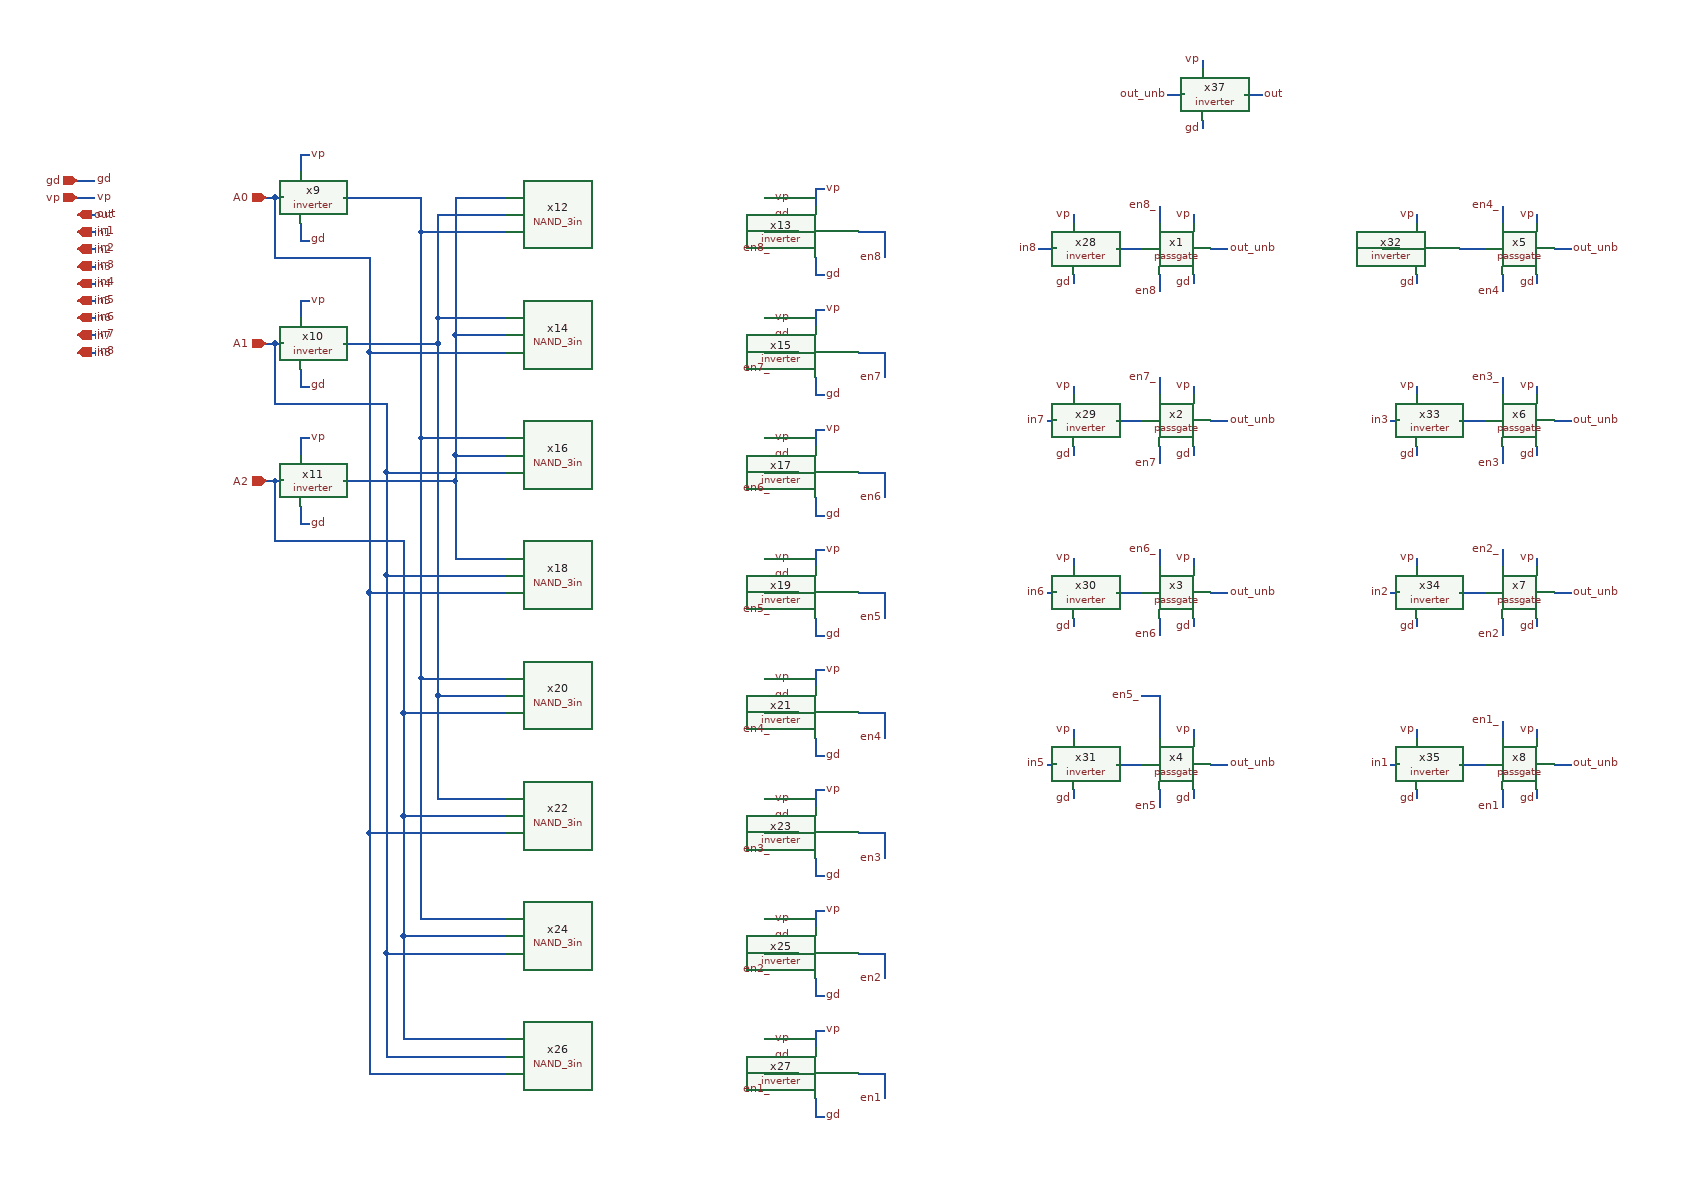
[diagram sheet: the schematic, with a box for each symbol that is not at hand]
v {xschem version=3.4.8RC file_version=1.3}
G {}
K {}
V {}
S {}
F {}
E {}
N -970 -290 -950 -290 {lab=gd}
N -970 -270 -950 -270 {lab=vp}
N -970 -250 -950 -250 {lab=out}
N -970 -230 -950 -230 {lab=in1}
N -970 -210 -950 -210 {lab=in2}
N -970 -190 -950 -190 {lab=in3}
N -970 -170 -950 -170 {lab=in4}
N -970 -130 -950 -130 {lab=in6}
N -970 -110 -950 -110 {lab=in7}
N -970 -90 -950 -90 {lab=in8}
N 290 -260 290 -240 {lab=en8_}
N 290 -180 290 -160 {lab=en8}
N 330 -180 330 -170 {lab=gd}
N 330 -250 330 -240 {lab=vp}
N 350 -210 370 -210 {lab=out_unb}
N 290 -60 290 -40 {lab=en7_}
N 290 20 290 40 {lab=en7}
N 330 20 330 30 {lab=gd}
N 330 -50 330 -40 {lab=vp}
N 160 -10 170 -10 {lab=in7}
N 350 -10 370 -10 {lab=out_unb}
N -970 -150 -950 -150 {lab=in5}
N 290 140 290 160 {lab=en6_}
N 290 220 290 240 {lab=en6}
N 330 220 330 230 {lab=gd}
N 330 150 330 160 {lab=vp}
N 160 190 170 190 {lab=in6}
N 350 190 370 190 {lab=out_unb}
N 290 420 290 440 {lab=en5}
N 330 420 330 430 {lab=gd}
N 330 350 330 360 {lab=vp}
N 160 390 170 390 {lab=in5}
N 350 390 370 390 {lab=out_unb}
N 690 -260 690 -240 {lab=en4_}
N 690 -180 690 -160 {lab=en4}
N 730 -180 730 -170 {lab=gd}
N 730 -250 730 -240 {lab=vp}
N 750 -210 770 -210 {lab=out_unb}
N 690 -60 690 -40 {lab=en3_}
N 690 20 690 40 {lab=en3}
N 730 20 730 30 {lab=gd}
N 730 -50 730 -40 {lab=vp}
N 560 -10 570 -10 {lab=in3}
N 750 -10 770 -10 {lab=out_unb}
N 690 140 690 160 {lab=en2_}
N 690 220 690 240 {lab=en2}
N 730 220 730 230 {lab=gd}
N 730 150 730 160 {lab=vp}
N 750 190 770 190 {lab=out_unb}
N 690 340 690 360 {lab=en1_}
N 690 420 690 440 {lab=en1}
N 730 420 730 430 {lab=gd}
N 730 350 730 360 {lab=vp}
N 750 390 770 390 {lab=out_unb}
N -710 -320 -700 -320 {lab=vp}
N -710 -320 -710 -300 {lab=vp}
N -710 -220 -700 -220 {lab=gd}
N -710 -240 -710 -220 {lab=gd}
N -740 -270 -730 -270 {lab=A0}
N -710 -150 -700 -150 {lab=vp}
N -710 -150 -710 -130 {lab=vp}
N -710 -50 -700 -50 {lab=gd}
N -710 -70 -710 -50 {lab=gd}
N -740 -100 -730 -100 {lab=A1}
N -710 10 -700 10 {lab=vp}
N -710 10 -710 30 {lab=vp}
N -710 110 -700 110 {lab=gd}
N -710 90 -710 110 {lab=gd}
N -740 60 -730 60 {lab=A2}
N -170 -270 -160 -270 {lab=vp}
N -170 -250 -160 -250 {lab=gd}
N -110 -280 -100 -280 {lab=vp}
N -110 -280 -110 -260 {lab=vp}
N -110 -180 -100 -180 {lab=gd}
N -110 -200 -110 -180 {lab=gd}
N -160 -230 -130 -230 {lab=en8_}
N -60 -230 -30 -230 {lab=en8}
N -160 -230 -160 -210 {lab=en8_}
N -170 -230 -160 -230 {lab=en8_}
N -30 -230 -30 -200 {lab=en8}
N -170 -130 -160 -130 {lab=vp}
N -170 -110 -160 -110 {lab=gd}
N -110 -140 -100 -140 {lab=vp}
N -110 -140 -110 -120 {lab=vp}
N -110 -40 -100 -40 {lab=gd}
N -110 -60 -110 -40 {lab=gd}
N -160 -90 -130 -90 {lab=en7_}
N -60 -90 -30 -90 {lab=en7}
N -160 -90 -160 -70 {lab=en7_}
N -170 -90 -160 -90 {lab=en7_}
N -30 -90 -30 -60 {lab=en7}
N -170 10 -160 10 {lab=vp}
N -170 30 -160 30 {lab=gd}
N -110 0 -100 0 {lab=vp}
N -110 0 -110 20 {lab=vp}
N -110 100 -100 100 {lab=gd}
N -110 80 -110 100 {lab=gd}
N -160 50 -130 50 {lab=en6_}
N -60 50 -30 50 {lab=en6}
N -160 50 -160 70 {lab=en6_}
N -170 50 -160 50 {lab=en6_}
N -30 50 -30 80 {lab=en6}
N -170 150 -160 150 {lab=vp}
N -170 170 -160 170 {lab=gd}
N -110 140 -100 140 {lab=vp}
N -110 140 -110 160 {lab=vp}
N -110 240 -100 240 {lab=gd}
N -110 220 -110 240 {lab=gd}
N -160 190 -130 190 {lab=en5_}
N -60 190 -30 190 {lab=en5}
N -160 190 -160 210 {lab=en5_}
N -170 190 -160 190 {lab=en5_}
N -30 190 -30 220 {lab=en5}
N -170 290 -160 290 {lab=vp}
N -170 310 -160 310 {lab=gd}
N -110 280 -100 280 {lab=vp}
N -110 280 -110 300 {lab=vp}
N -110 380 -100 380 {lab=gd}
N -110 360 -110 380 {lab=gd}
N -160 330 -130 330 {lab=en4_}
N -60 330 -30 330 {lab=en4}
N -160 330 -160 350 {lab=en4_}
N -170 330 -160 330 {lab=en4_}
N -30 330 -30 360 {lab=en4}
N -170 430 -160 430 {lab=vp}
N -170 450 -160 450 {lab=gd}
N -110 420 -100 420 {lab=vp}
N -110 420 -110 440 {lab=vp}
N -110 520 -100 520 {lab=gd}
N -110 500 -110 520 {lab=gd}
N -160 470 -130 470 {lab=en3_}
N -60 470 -30 470 {lab=en3}
N -160 470 -160 490 {lab=en3_}
N -170 470 -160 470 {lab=en3_}
N -30 470 -30 500 {lab=en3}
N -170 570 -160 570 {lab=vp}
N -170 590 -160 590 {lab=gd}
N -110 560 -100 560 {lab=vp}
N -110 560 -110 580 {lab=vp}
N -110 660 -100 660 {lab=gd}
N -110 640 -110 660 {lab=gd}
N -160 610 -130 610 {lab=en2_}
N -60 610 -30 610 {lab=en2}
N -160 610 -160 630 {lab=en2_}
N -170 610 -160 610 {lab=en2_}
N -30 610 -30 640 {lab=en2}
N -170 710 -160 710 {lab=vp}
N -170 730 -160 730 {lab=gd}
N -110 700 -100 700 {lab=vp}
N -110 700 -110 720 {lab=vp}
N -110 800 -100 800 {lab=gd}
N -110 780 -110 800 {lab=gd}
N -160 750 -130 750 {lab=en1_}
N -60 750 -30 750 {lab=en1}
N -160 750 -160 770 {lab=en1_}
N -170 750 -160 750 {lab=en1_}
N -30 750 -30 780 {lab=en1}
N -630 470 -630 750 {lab=A0}
N -740 -270 -740 -200 {lab=A0}
N -750 -270 -740 -270 {lab=A0}
N -740 -200 -630 -200 {lab=A0}
N -740 -100 -740 -30 {lab=A1}
N -750 -100 -740 -100 {lab=A1}
N -740 -30 -610 -30 {lab=A1}
N -740 60 -740 130 {lab=A2}
N -750 60 -740 60 {lab=A2}
N -740 130 -590 130 {lab=A2}
N -660 -270 -570 -270 {lab=#net1}
N -660 -100 -550 -100 {lab=#net2}
N -550 -130 -550 -100 {lab=#net2}
N -660 60 -530 60 {lab=#net3}
N -530 30 -530 60 {lab=#net3}
N -570 -230 -470 -230 {lab=#net1}
N -570 -270 -570 -230 {lab=#net1}
N -550 -250 -470 -250 {lab=#net2}
N -530 -270 -470 -270 {lab=#net3}
N -570 10 -470 10 {lab=#net1}
N -570 -230 -570 10 {lab=#net1}
N -570 290 -470 290 {lab=#net1}
N -570 10 -570 290 {lab=#net1}
N -570 570 -470 570 {lab=#net1}
N -570 290 -570 570 {lab=#net1}
N -550 -130 -470 -130 {lab=#net2}
N -550 -250 -550 -130 {lab=#net2}
N -550 430 -470 430 {lab=#net2}
N -550 310 -550 430 {lab=#net2}
N -550 310 -470 310 {lab=#net2}
N -550 -100 -550 310 {lab=#net2}
N -530 -110 -470 -110 {lab=#net3}
N -530 -270 -530 -110 {lab=#net3}
N -530 30 -470 30 {lab=#net3}
N -530 -110 -530 30 {lab=#net3}
N -530 150 -470 150 {lab=#net3}
N -530 60 -530 150 {lab=#net3}
N -590 710 -470 710 {lab=A2}
N -590 590 -590 710 {lab=A2}
N -590 590 -470 590 {lab=A2}
N -590 450 -590 590 {lab=A2}
N -590 450 -470 450 {lab=A2}
N -590 330 -590 450 {lab=A2}
N -590 330 -470 330 {lab=A2}
N -590 130 -590 330 {lab=A2}
N -610 730 -470 730 {lab=A1}
N -610 610 -610 730 {lab=A1}
N -610 610 -470 610 {lab=A1}
N -610 170 -610 610 {lab=A1}
N -610 50 -470 50 {lab=A1}
N -610 -30 -610 50 {lab=A1}
N -610 170 -470 170 {lab=A1}
N -610 50 -610 170 {lab=A1}
N -630 -90 -470 -90 {lab=A0}
N -630 -200 -630 -90 {lab=A0}
N -630 190 -470 190 {lab=A0}
N -630 -90 -630 190 {lab=A0}
N -630 470 -470 470 {lab=A0}
N -630 190 -630 470 {lab=A0}
N -630 750 -470 750 {lab=A0}
N 240 -210 270 -210 {lab=#net4}
N 190 -250 190 -240 {lab=vp}
N 190 -180 190 -170 {lab=gd}
N 150 -210 170 -210 {lab=in8}
N 240 -10 270 -10 {lab=#net5}
N 190 -50 190 -40 {lab=vp}
N 190 20 190 30 {lab=gd}
N 240 190 270 190 {lab=#net6}
N 190 150 190 160 {lab=vp}
N 190 220 190 230 {lab=gd}
N 240 390 270 390 {lab=#net7}
N 190 350 190 360 {lab=vp}
N 190 420 190 430 {lab=gd}
N 560 190 570 190 {lab=in2}
N 560 390 570 390 {lab=in1}
N 640 -210 670 -210 {lab=#net8}
N 590 -250 590 -240 {lab=vp}
N 590 -180 590 -170 {lab=gd}
N 550 -210 570 -210 {lab=in4}
N 640 -10 670 -10 {lab=#net9}
N 590 -50 590 -40 {lab=vp}
N 590 20 590 30 {lab=gd}
N 640 190 670 190 {lab=#net10}
N 590 150 590 160 {lab=vp}
N 590 220 590 230 {lab=gd}
N 640 390 670 390 {lab=#net11}
N 590 350 590 360 {lab=vp}
N 590 420 590 430 {lab=gd}
N 340 -430 340 -420 {lab=vp}
N 340 -360 340 -350 {lab=gd}
N 390 -390 410 -390 {lab=out}
N 300 -390 320 -390 {lab=out_unb}
N 270 310 290 310 {lab=en5_}
N 290 310 290 360 {lab=en5_}
C {/foss/designs/CHIP-PLL/divider/schematics/passgate.sym} 290 -190 0 0 {name=x1}
C {iopin.sym} -970 -290 2 0 {name=p1 lab=gd}
C {lab_pin.sym} -950 -290 2 0 {name=p4 sig_type=std_logic lab=gd}
C {iopin.sym} -970 -270 2 0 {name=p5 lab=vp}
C {lab_pin.sym} -950 -270 2 0 {name=p6 sig_type=std_logic lab=vp}
C {opin.sym} -970 -250 2 0 {name=p2 lab=out}
C {lab_pin.sym} -950 -250 2 0 {name=p3 sig_type=std_logic lab=out}
C {ipin.sym} -970 -230 2 1 {name=p7 lab=in1}
C {lab_pin.sym} -950 -230 2 0 {name=p8 sig_type=std_logic lab=in1}
C {ipin.sym} -970 -210 2 1 {name=p9 lab=in2}
C {lab_pin.sym} -950 -210 2 0 {name=p10 sig_type=std_logic lab=in2}
C {ipin.sym} -970 -190 2 1 {name=p11 lab=in3}
C {lab_pin.sym} -950 -190 2 0 {name=p12 sig_type=std_logic lab=in3}
C {ipin.sym} -970 -170 2 1 {name=p13 lab=in4}
C {lab_pin.sym} -950 -170 2 0 {name=p14 sig_type=std_logic lab=in4}
C {ipin.sym} -970 -150 2 1 {name=p15 lab=in5}
C {lab_pin.sym} -950 -150 2 0 {name=p16 sig_type=std_logic lab=in5}
C {ipin.sym} -970 -130 2 1 {name=p17 lab=in6}
C {lab_pin.sym} -950 -130 2 0 {name=p18 sig_type=std_logic lab=in6}
C {ipin.sym} -970 -110 2 1 {name=p19 lab=in7}
C {lab_pin.sym} -950 -110 2 0 {name=p20 sig_type=std_logic lab=in7}
C {ipin.sym} -970 -90 2 1 {name=p21 lab=in8}
C {lab_pin.sym} -950 -90 2 0 {name=p22 sig_type=std_logic lab=in8}
C {lab_pin.sym} 330 -170 3 0 {name=p23 sig_type=std_logic lab=gd}
C {lab_pin.sym} 290 -260 1 0 {name=p25 sig_type=std_logic lab=en8_}
C {lab_pin.sym} 290 -160 3 0 {name=p26 sig_type=std_logic lab=en8}
C {lab_pin.sym} 150 -210 0 0 {name=p27 sig_type=std_logic lab=in8}
C {lab_pin.sym} 370 -210 2 0 {name=p28 sig_type=std_logic lab=out_unb}
C {/foss/designs/CHIP-PLL/divider/schematics/passgate.sym} 290 10 0 0 {name=x2}
C {lab_pin.sym} 330 30 3 0 {name=p29 sig_type=std_logic lab=gd}
C {lab_pin.sym} 290 -60 1 0 {name=p31 sig_type=std_logic lab=en7_}
C {lab_pin.sym} 290 40 3 0 {name=p32 sig_type=std_logic lab=en7}
C {lab_pin.sym} 160 -10 0 0 {name=p33 sig_type=std_logic lab=in7}
C {lab_pin.sym} 370 -10 2 0 {name=p34 sig_type=std_logic lab=out_unb}
C {/foss/designs/CHIP-PLL/divider/schematics/passgate.sym} 290 210 0 0 {name=x3}
C {lab_pin.sym} 330 230 3 0 {name=p35 sig_type=std_logic lab=gd}
C {lab_pin.sym} 290 140 1 0 {name=p37 sig_type=std_logic lab=en6_}
C {lab_pin.sym} 290 240 3 0 {name=p38 sig_type=std_logic lab=en6}
C {lab_pin.sym} 160 190 0 0 {name=p39 sig_type=std_logic lab=in6
}
C {lab_pin.sym} 370 190 2 0 {name=p40 sig_type=std_logic lab=out_unb}
C {/foss/designs/CHIP-PLL/divider/schematics/passgate.sym} 290 410 0 0 {name=x4}
C {lab_pin.sym} 330 430 3 0 {name=p41 sig_type=std_logic lab=gd}
C {lab_pin.sym} 290 440 3 0 {name=p44 sig_type=std_logic lab=en5}
C {lab_pin.sym} 160 390 0 0 {name=p45 sig_type=std_logic lab=in5}
C {lab_pin.sym} 370 390 2 0 {name=p46 sig_type=std_logic lab=out_unb}
C {/foss/designs/CHIP-PLL/divider/schematics/passgate.sym} 690 -190 0 0 {name=x5}
C {lab_pin.sym} 730 -170 3 0 {name=p47 sig_type=std_logic lab=gd}
C {lab_pin.sym} 690 -260 1 0 {name=p49 sig_type=std_logic lab=en4_}
C {lab_pin.sym} 690 -160 3 0 {name=p50 sig_type=std_logic lab=en4}
C {lab_pin.sym} 560 -210 0 0 {name=p51 sig_type=std_logic lab=in4}
C {lab_pin.sym} 770 -210 2 0 {name=p52 sig_type=std_logic lab=out_unb}
C {/foss/designs/CHIP-PLL/divider/schematics/passgate.sym} 690 10 0 0 {name=x6}
C {lab_pin.sym} 730 30 3 0 {name=p53 sig_type=std_logic lab=gd}
C {lab_pin.sym} 690 -60 1 0 {name=p55 sig_type=std_logic lab=en3_}
C {lab_pin.sym} 690 40 3 0 {name=p56 sig_type=std_logic lab=en3}
C {lab_pin.sym} 560 -10 0 0 {name=p57 sig_type=std_logic lab=in3}
C {lab_pin.sym} 770 -10 2 0 {name=p58 sig_type=std_logic lab=out_unb}
C {/foss/designs/CHIP-PLL/divider/schematics/passgate.sym} 690 210 0 0 {name=x7}
C {lab_pin.sym} 730 230 3 0 {name=p59 sig_type=std_logic lab=gd}
C {lab_pin.sym} 690 140 1 0 {name=p61 sig_type=std_logic lab=en2_}
C {lab_pin.sym} 690 240 3 0 {name=p62 sig_type=std_logic lab=en2}
C {lab_pin.sym} 560 190 0 0 {name=p63 sig_type=std_logic lab=in2}
C {lab_pin.sym} 770 190 2 0 {name=p64 sig_type=std_logic lab=out_unb}
C {/foss/designs/CHIP-PLL/divider/schematics/passgate.sym} 690 410 0 0 {name=x8}
C {lab_pin.sym} 730 430 3 0 {name=p65 sig_type=std_logic lab=gd}
C {lab_pin.sym} 690 340 1 0 {name=p67 sig_type=std_logic lab=en1_
_}
C {lab_pin.sym} 690 440 3 0 {name=p68 sig_type=std_logic lab=en1}
C {lab_pin.sym} 560 390 0 0 {name=p69 sig_type=std_logic lab=in1}
C {lab_pin.sym} 770 390 2 0 {name=p70 sig_type=std_logic lab=out_unb}
C {/foss/designs/CHIP-PLL/divider/schematics/inverter.sym} -710 -270 0 0 {name=x9}
C {lab_pin.sym} -700 -220 2 0 {name=p71 sig_type=std_logic lab=gd}
C {lab_pin.sym} -700 -320 2 0 {name=p72 sig_type=std_logic lab=vp}
C {ipin.sym} -750 -270 0 0 {name=p73 lab=A0}
C {/foss/designs/CHIP-PLL/divider/schematics/inverter.sym} -710 -100 0 0 {name=x10}
C {lab_pin.sym} -700 -50 2 0 {name=p74 sig_type=std_logic lab=gd}
C {lab_pin.sym} -700 -150 2 0 {name=p75 sig_type=std_logic lab=vp}
C {ipin.sym} -750 -100 0 0 {name=p76 lab=A1}
C {/foss/designs/CHIP-PLL/divider/schematics/inverter.sym} -710 60 0 0 {name=x11}
C {lab_pin.sym} -700 110 2 0 {name=p77 sig_type=std_logic lab=gd}
C {lab_pin.sym} -700 10 2 0 {name=p78 sig_type=std_logic lab=vp}
C {ipin.sym} -750 60 0 0 {name=p79 lab=A2}
C {lab_pin.sym} 330 -250 1 0 {name=p24 sig_type=std_logic lab=vp}
C {lab_pin.sym} 730 -250 1 0 {name=p30 sig_type=std_logic lab=vp}
C {lab_pin.sym} 330 -50 1 0 {name=p36 sig_type=std_logic lab=vp}
C {lab_pin.sym} 730 -50 1 0 {name=p42 sig_type=std_logic lab=vp}
C {lab_pin.sym} 330 150 1 0 {name=p48 sig_type=std_logic lab=vp}
C {lab_pin.sym} 730 150 1 0 {name=p54 sig_type=std_logic lab=vp}
C {lab_pin.sym} 330 350 1 0 {name=p60 sig_type=std_logic lab=vp}
C {lab_pin.sym} 730 350 1 0 {name=p66 sig_type=std_logic lab=vp}
C {lab_pin.sym} -160 -270 2 0 {name=p80 sig_type=std_logic lab=vp}
C {lab_pin.sym} -160 -250 2 0 {name=p81 sig_type=std_logic lab=gd}
C {/foss/designs/CHIP-PLL/divider/schematics/inverter.sym} -110 -230 0 0 {name=x13}
C {lab_pin.sym} -100 -180 2 0 {name=p82 sig_type=std_logic lab=gd}
C {lab_pin.sym} -100 -280 2 0 {name=p83 sig_type=std_logic lab=vp}
C {lab_pin.sym} -160 -210 3 0 {name=p84 sig_type=std_logic lab=en8_}
C {lab_pin.sym} -30 -200 3 0 {name=p85 sig_type=std_logic lab=en8}
C {lab_pin.sym} -160 -130 2 0 {name=p86 sig_type=std_logic lab=vp}
C {lab_pin.sym} -160 -110 2 0 {name=p87 sig_type=std_logic lab=gd}
C {/foss/designs/CHIP-PLL/divider/schematics/inverter.sym} -110 -90 0 0 {name=x15}
C {lab_pin.sym} -100 -40 2 0 {name=p88 sig_type=std_logic lab=gd}
C {lab_pin.sym} -100 -140 2 0 {name=p89 sig_type=std_logic lab=vp}
C {lab_pin.sym} -160 -70 3 0 {name=p90 sig_type=std_logic lab=en7_}
C {lab_pin.sym} -30 -60 3 0 {name=p91 sig_type=std_logic lab=en7}
C {lab_pin.sym} -160 10 2 0 {name=p92 sig_type=std_logic lab=vp}
C {lab_pin.sym} -160 30 2 0 {name=p93 sig_type=std_logic lab=gd}
C {/foss/designs/CHIP-PLL/divider/schematics/inverter.sym} -110 50 0 0 {name=x17}
C {lab_pin.sym} -100 100 2 0 {name=p94 sig_type=std_logic lab=gd}
C {lab_pin.sym} -100 0 2 0 {name=p95 sig_type=std_logic lab=vp}
C {lab_pin.sym} -160 70 3 0 {name=p96 sig_type=std_logic lab=en6_}
C {lab_pin.sym} -30 80 3 0 {name=p97 sig_type=std_logic lab=en6}
C {lab_pin.sym} -160 150 2 0 {name=p98 sig_type=std_logic lab=vp}
C {lab_pin.sym} -160 170 2 0 {name=p99 sig_type=std_logic lab=gd}
C {/foss/designs/CHIP-PLL/divider/schematics/inverter.sym} -110 190 0 0 {name=x19}
C {lab_pin.sym} -100 240 2 0 {name=p100 sig_type=std_logic lab=gd}
C {lab_pin.sym} -100 140 2 0 {name=p101 sig_type=std_logic lab=vp}
C {lab_pin.sym} -160 210 3 0 {name=p102 sig_type=std_logic lab=en5_}
C {lab_pin.sym} -30 220 3 0 {name=p103 sig_type=std_logic lab=en5}
C {lab_pin.sym} -160 290 2 0 {name=p104 sig_type=std_logic lab=vp}
C {lab_pin.sym} -160 310 2 0 {name=p105 sig_type=std_logic lab=gd}
C {/foss/designs/CHIP-PLL/divider/schematics/inverter.sym} -110 330 0 0 {name=x21}
C {lab_pin.sym} -100 380 2 0 {name=p106 sig_type=std_logic lab=gd}
C {lab_pin.sym} -100 280 2 0 {name=p107 sig_type=std_logic lab=vp}
C {lab_pin.sym} -160 350 3 0 {name=p108 sig_type=std_logic lab=en4_}
C {lab_pin.sym} -30 360 3 0 {name=p109 sig_type=std_logic lab=en4}
C {lab_pin.sym} -160 430 2 0 {name=p110 sig_type=std_logic lab=vp}
C {lab_pin.sym} -160 450 2 0 {name=p111 sig_type=std_logic lab=gd}
C {/foss/designs/CHIP-PLL/divider/schematics/inverter.sym} -110 470 0 0 {name=x23}
C {lab_pin.sym} -100 520 2 0 {name=p112 sig_type=std_logic lab=gd}
C {lab_pin.sym} -100 420 2 0 {name=p113 sig_type=std_logic lab=vp}
C {lab_pin.sym} -160 490 3 0 {name=p114 sig_type=std_logic lab=en3_}
C {lab_pin.sym} -30 500 3 0 {name=p115 sig_type=std_logic lab=en3}
C {lab_pin.sym} -160 570 2 0 {name=p116 sig_type=std_logic lab=vp}
C {lab_pin.sym} -160 590 2 0 {name=p117 sig_type=std_logic lab=gd}
C {/foss/designs/CHIP-PLL/divider/schematics/inverter.sym} -110 610 0 0 {name=x25}
C {lab_pin.sym} -100 660 2 0 {name=p118 sig_type=std_logic lab=gd}
C {lab_pin.sym} -100 560 2 0 {name=p119 sig_type=std_logic lab=vp}
C {lab_pin.sym} -160 630 3 0 {name=p120 sig_type=std_logic lab=en2_}
C {lab_pin.sym} -30 640 3 0 {name=p121 sig_type=std_logic lab=en2}
C {lab_pin.sym} -160 710 2 0 {name=p122 sig_type=std_logic lab=vp}
C {lab_pin.sym} -160 730 2 0 {name=p123 sig_type=std_logic lab=gd}
C {/foss/designs/CHIP-PLL/divider/schematics/inverter.sym} -110 750 0 0 {name=x27}
C {lab_pin.sym} -100 800 2 0 {name=p124 sig_type=std_logic lab=gd}
C {lab_pin.sym} -100 700 2 0 {name=p125 sig_type=std_logic lab=vp}
C {lab_pin.sym} -160 770 3 0 {name=p126 sig_type=std_logic lab=en1_}
C {lab_pin.sym} -30 780 3 0 {name=p127 sig_type=std_logic lab=en1}
C {/foss/designs/CHIP-PLL/divider/schematics/inverter.sym} 190 -210 0 0 {name=x28}
C {lab_pin.sym} 190 -250 1 0 {name=p136 sig_type=std_logic lab=vp}
C {lab_pin.sym} 190 -170 3 0 {name=p137 sig_type=std_logic lab=gd}
C {/foss/designs/CHIP-PLL/divider/schematics/inverter.sym} 190 -10 0 0 {name=x29}
C {lab_pin.sym} 190 -50 1 0 {name=p138 sig_type=std_logic lab=vp}
C {lab_pin.sym} 190 30 3 0 {name=p139 sig_type=std_logic lab=gd}
C {/foss/designs/CHIP-PLL/divider/schematics/inverter.sym} 190 190 0 0 {name=x30}
C {lab_pin.sym} 190 150 1 0 {name=p140 sig_type=std_logic lab=vp}
C {lab_pin.sym} 190 230 3 0 {name=p141 sig_type=std_logic lab=gd}
C {/foss/designs/CHIP-PLL/divider/schematics/inverter.sym} 190 390 0 0 {name=x31}
C {lab_pin.sym} 190 350 1 0 {name=p142 sig_type=std_logic lab=vp}
C {lab_pin.sym} 190 430 3 0 {name=p143 sig_type=std_logic lab=gd}
C {/foss/designs/CHIP-PLL/divider/schematics/inverter.sym} 590 -210 0 0 {name=x32}
C {lab_pin.sym} 590 -250 1 0 {name=p144 sig_type=std_logic lab=vp}
C {lab_pin.sym} 590 -170 3 0 {name=p145 sig_type=std_logic lab=gd}
C {/foss/designs/CHIP-PLL/divider/schematics/inverter.sym} 590 -10 0 0 {name=x33}
C {lab_pin.sym} 590 -50 1 0 {name=p146 sig_type=std_logic lab=vp}
C {lab_pin.sym} 590 30 3 0 {name=p147 sig_type=std_logic lab=gd}
C {/foss/designs/CHIP-PLL/divider/schematics/inverter.sym} 590 190 0 0 {name=x34}
C {lab_pin.sym} 590 150 1 0 {name=p148 sig_type=std_logic lab=vp}
C {lab_pin.sym} 590 230 3 0 {name=p149 sig_type=std_logic lab=gd}
C {/foss/designs/CHIP-PLL/divider/schematics/inverter.sym} 590 390 0 0 {name=x35}
C {lab_pin.sym} 590 350 1 0 {name=p150 sig_type=std_logic lab=vp}
C {lab_pin.sym} 590 430 3 0 {name=p151 sig_type=std_logic lab=gd}
C {lab_pin.sym} 340 -430 1 0 {name=p152 sig_type=std_logic lab=vp}
C {lab_pin.sym} 340 -350 3 0 {name=p153 sig_type=std_logic lab=gd}
C {lab_pin.sym} 410 -390 2 0 {name=p154 sig_type=std_logic lab=out}
C {lab_pin.sym} 300 -390 0 0 {name=p155 sig_type=std_logic lab=out_unb}
C {/foss/designs/CHIP-PLL/divider/schematics/NAND_3in.sym} -320 -250 0 0 {name=x12}
C {/foss/designs/CHIP-PLL/divider/schematics/NAND_3in.sym} -320 -110 0 0 {name=x14}
C {/foss/designs/CHIP-PLL/divider/schematics/NAND_3in.sym} -320 30 0 0 {name=x16}
C {/foss/designs/CHIP-PLL/divider/schematics/NAND_3in.sym} -320 170 0 0 {name=x18}
C {/foss/designs/CHIP-PLL/divider/schematics/NAND_3in.sym} -320 310 0 0 {name=x20}
C {/foss/designs/CHIP-PLL/divider/schematics/NAND_3in.sym} -320 450 0 0 {name=x22}
C {/foss/designs/CHIP-PLL/divider/schematics/NAND_3in.sym} -320 590 0 0 {name=x24}
C {/foss/designs/CHIP-PLL/divider/schematics/NAND_3in.sym} -320 730 0 0 {name=x26}
C {/foss/designs/CHIP-PLL/divider/schematics/inverter.sym} 340 -390 0 0 {name=x37}
C {lab_pin.sym} 270 310 3 0 {name=p43 sig_type=std_logic lab=en5_}
